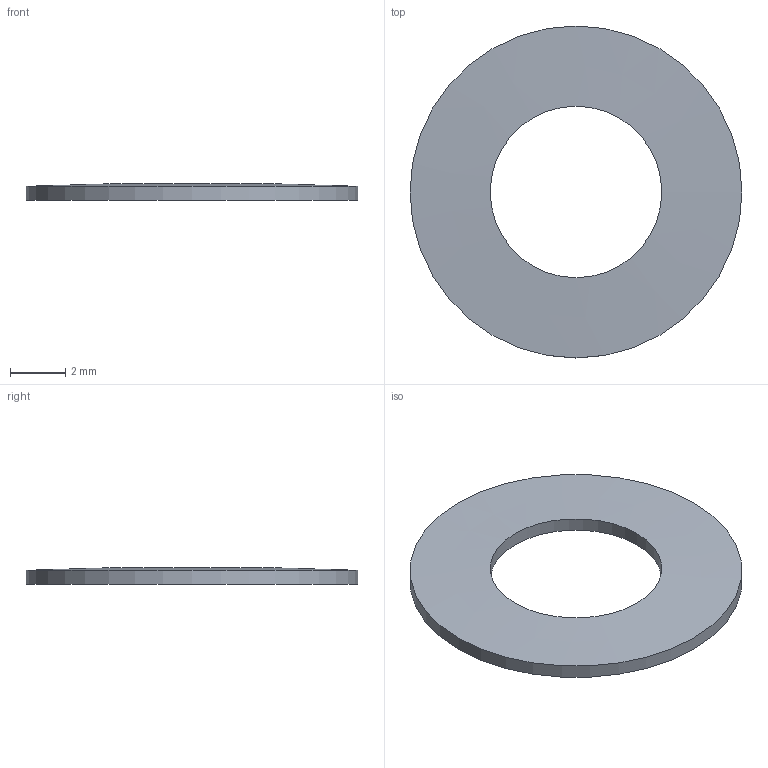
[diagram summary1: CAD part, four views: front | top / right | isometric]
STEP (ISO 10303-21) file: header records copied from the file, then geometry measured from it (millimetres).
FILE_DESCRIPTION(('Open CASCADE Model'),'2;1');
FILE_NAME('Open CASCADE Shape Model','2026-09-24T17:43:00',('Author'),( 'Open CASCADE'),'Open CASCADE STEP processor 7.8','Open CASCADE 7.8' ,'Unknown');
FILE_SCHEMA(('AUTOMOTIVE_DESIGN { 1 0 10303 214 1 1 1 1 }'));
Length unit declared in the file: millimetre
Products named in the file (1): Open CASCADE STEP translator 7.8 17
Bounding box: 12 x 12 x 0.59 mm (x, y, z)
Volume: 41.5 mm3; surface area: 194.5 mm2
Topology: 1 solids, 1 shells, 4 faces, 8 edges, 4 vertices
Faces by surface type: cone 2, cylinder 2
Full cylindrical faces by diameter (mm): 6.2 x1, 12 x1
Entity records: 222 total; most frequent: DIRECTION 38, CARTESIAN_POINT 33, LINE 20, VECTOR 20, ORIENTED_EDGE 16, PCURVE 16, DEFINITIONAL_REPRESENTATION 16, AXIS2_PLACEMENT_3D 9
One B-rep face of a CAD part: STEP entity #160.
In plain terms, the conical face has half-angle 88.272 degrees and reference radius 6 mm.
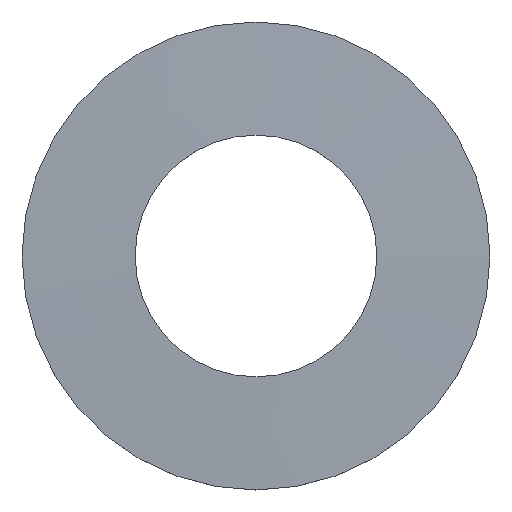
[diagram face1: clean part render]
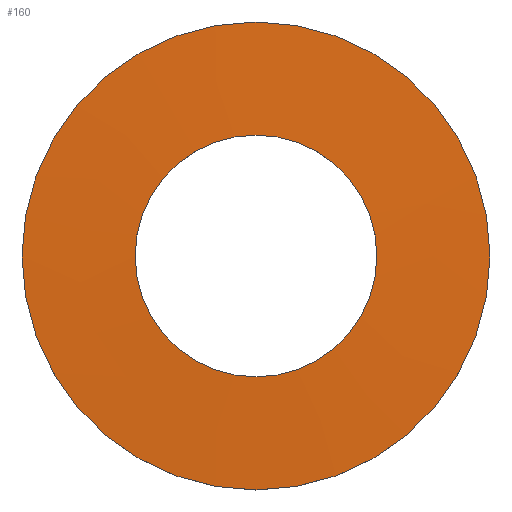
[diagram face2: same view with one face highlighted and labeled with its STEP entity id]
Its self-contained STEP definition (entity closure, numbers rounded to 3 decimals):
#66 = CYLINDRICAL_SURFACE('',#67,6.);
#67 = AXIS2_PLACEMENT_3D('',#68,#69,#70);
#68 = CARTESIAN_POINT('',(0.,0.,-7.775));
#69 = DIRECTION('',(0.,0.,1.));
#70 = DIRECTION('',(1.,0.,-0.));
#94 = CYLINDRICAL_SURFACE('',#95,3.1);
#95 = AXIS2_PLACEMENT_3D('',#96,#97,#98);
#96 = CARTESIAN_POINT('',(0.,0.,-7.188));
#97 = DIRECTION('',(-0.,-0.,-1.));
#98 = DIRECTION('',(1.,0.,0.));
#111 = VERTEX_POINT('',#112);
#112 = CARTESIAN_POINT('',(6.,0.,-7.275));
#133 = EDGE_CURVE('',#111,#111,#134,.T.);
#134 = SURFACE_CURVE('',#135,(#140,#147),.PCURVE_S1.);
#135 = CIRCLE('',#136,6.);
#136 = AXIS2_PLACEMENT_3D('',#137,#138,#139);
#137 = CARTESIAN_POINT('',(0.,0.,-7.275));
#138 = DIRECTION('',(0.,0.,1.));
#139 = DIRECTION('',(1.,0.,-0.));
#140 = PCURVE('',#66,#141);
#141 = DEFINITIONAL_REPRESENTATION('',(#142),#146);
#142 = LINE('',#143,#144);
#143 = CARTESIAN_POINT('',(0.,0.5));
#144 = VECTOR('',#145,1.);
#145 = DIRECTION('',(1.,0.));
#146 = ( GEOMETRIC_REPRESENTATION_CONTEXT(2) 
PARAMETRIC_REPRESENTATION_CONTEXT() REPRESENTATION_CONTEXT('2D SPACE',''
  ) );
#147 = PCURVE('',#148,#153);
#148 = CONICAL_SURFACE('',#149,6.,1.541);
#149 = AXIS2_PLACEMENT_3D('',#150,#151,#152);
#150 = CARTESIAN_POINT('',(0.,0.,-7.275));
#151 = DIRECTION('',(-0.,-0.,-1.));
#152 = DIRECTION('',(1.,0.,-0.));
#153 = DEFINITIONAL_REPRESENTATION('',(#154),#158);
#154 = LINE('',#155,#156);
#155 = CARTESIAN_POINT('',(6.283,0.));
#156 = VECTOR('',#157,1.);
#157 = DIRECTION('',(-1.,0.));
#158 = ( GEOMETRIC_REPRESENTATION_CONTEXT(2) 
PARAMETRIC_REPRESENTATION_CONTEXT() REPRESENTATION_CONTEXT('2D SPACE',''
  ) );
#160 = ADVANCED_FACE('',(#161),#148,.T.);
#161 = FACE_BOUND('',#162,.T.);
#162 = EDGE_LOOP('',(#163,#164,#187,#209));
#163 = ORIENTED_EDGE('',*,*,#133,.T.);
#164 = ORIENTED_EDGE('',*,*,#165,.T.);
#165 = EDGE_CURVE('',#111,#166,#168,.T.);
#166 = VERTEX_POINT('',#167);
#167 = CARTESIAN_POINT('',(3.1,0.,-7.188));
#168 = SEAM_CURVE('',#169,(#173,#180),.PCURVE_S1.);
#169 = LINE('',#170,#171);
#170 = CARTESIAN_POINT('',(6.,0.,-7.275));
#171 = VECTOR('',#172,1.);
#172 = DIRECTION('',(-1.,0.,0.03));
#173 = PCURVE('',#148,#174);
#174 = DEFINITIONAL_REPRESENTATION('',(#175),#179);
#175 = LINE('',#176,#177);
#176 = CARTESIAN_POINT('',(0.,0.));
#177 = VECTOR('',#178,1.);
#178 = DIRECTION('',(-0.,-1.));
#179 = ( GEOMETRIC_REPRESENTATION_CONTEXT(2) 
PARAMETRIC_REPRESENTATION_CONTEXT() REPRESENTATION_CONTEXT('2D SPACE',''
  ) );
#180 = PCURVE('',#148,#181);
#181 = DEFINITIONAL_REPRESENTATION('',(#182),#186);
#182 = LINE('',#183,#184);
#183 = CARTESIAN_POINT('',(6.283,0.));
#184 = VECTOR('',#185,1.);
#185 = DIRECTION('',(-0.,-1.));
#186 = ( GEOMETRIC_REPRESENTATION_CONTEXT(2) 
PARAMETRIC_REPRESENTATION_CONTEXT() REPRESENTATION_CONTEXT('2D SPACE',''
  ) );
#187 = ORIENTED_EDGE('',*,*,#188,.F.);
#188 = EDGE_CURVE('',#166,#166,#189,.T.);
#189 = SURFACE_CURVE('',#190,(#195,#202),.PCURVE_S1.);
#190 = CIRCLE('',#191,3.1);
#191 = AXIS2_PLACEMENT_3D('',#192,#193,#194);
#192 = CARTESIAN_POINT('',(0.,0.,-7.188));
#193 = DIRECTION('',(0.,0.,1.));
#194 = DIRECTION('',(1.,0.,-0.));
#195 = PCURVE('',#148,#196);
#196 = DEFINITIONAL_REPRESENTATION('',(#197),#201);
#197 = LINE('',#198,#199);
#198 = CARTESIAN_POINT('',(6.283,-0.087));
#199 = VECTOR('',#200,1.);
#200 = DIRECTION('',(-1.,0.));
#201 = ( GEOMETRIC_REPRESENTATION_CONTEXT(2) 
PARAMETRIC_REPRESENTATION_CONTEXT() REPRESENTATION_CONTEXT('2D SPACE',''
  ) );
#202 = PCURVE('',#94,#203);
#203 = DEFINITIONAL_REPRESENTATION('',(#204),#208);
#204 = LINE('',#205,#206);
#205 = CARTESIAN_POINT('',(6.283,0.));
#206 = VECTOR('',#207,1.);
#207 = DIRECTION('',(-1.,0.));
#208 = ( GEOMETRIC_REPRESENTATION_CONTEXT(2) 
PARAMETRIC_REPRESENTATION_CONTEXT() REPRESENTATION_CONTEXT('2D SPACE',''
  ) );
#209 = ORIENTED_EDGE('',*,*,#165,.F.);
